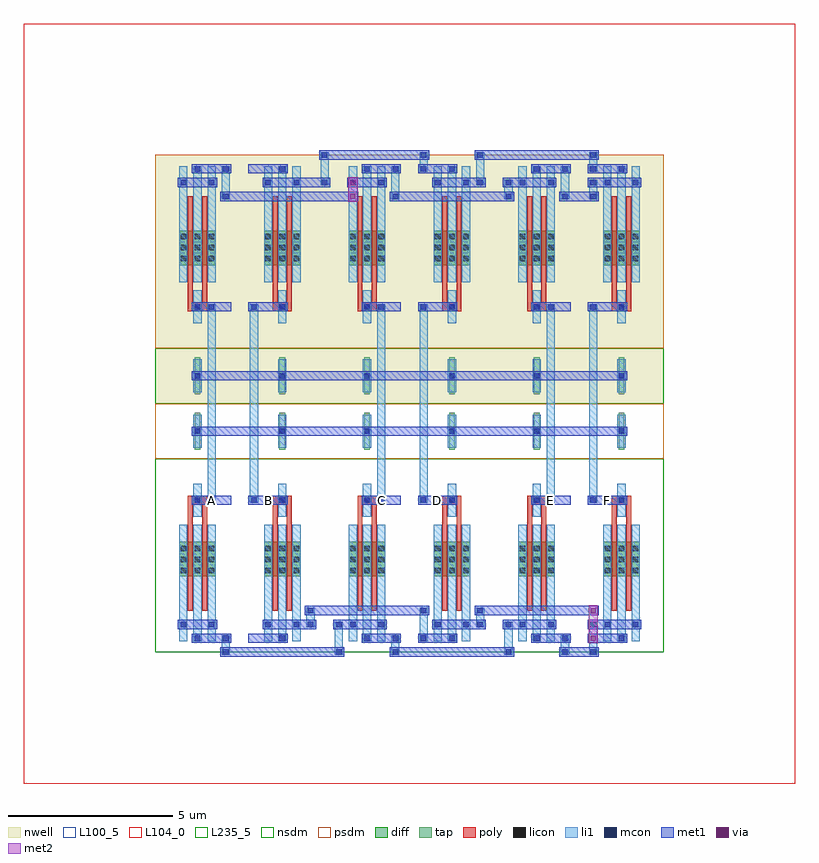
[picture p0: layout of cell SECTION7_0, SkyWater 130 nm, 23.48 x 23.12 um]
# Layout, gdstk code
from math import pi, radians
import gdstk
lib = gdstk.Library(unit=1e-6, precision=1e-09)
def R(c, l, rs):  # rectangles x0, y0, x1, y1
    for r in rs: c.add(gdstk.rectangle(r[:2], r[2:], *l))
def A(c, l, x, y, w, h, nx, ny, dx, dy):  # array of equal rectangles
    R(c, l, [(x+i*dx, y+j*dy, x+i*dx+w, y+j*dy+h) for i in range(nx) for j in range(ny)])
def P(c, l, *ps):  # polygons
    for p in ps: c.add(gdstk.Polygon(p, *l))
nwell = (64, 20)
diff = (65, 20)
tap = (65, 44)
poly = (66, 20)
licon = (66, 44)
li1 = (67, 20)
mcon = (67, 44)
met1 = (68, 20)
via = (68, 44)
met2 = (69, 20)
nsdm = (93, 44)
psdm = (94, 20)
L100_5 = (100, 5)
L104_0 = (104, 0)
L235_5 = (235, 5)

nmos_4t_81744335_x1_y1_1 = lib.new_cell('NMOS_4T_81744335_X1_Y1_1676685742')
R(nmos_4t_81744335_x1_y1_1, diff, [(0.735,2.31,1.845,3.36)])
R(nmos_4t_81744335_x1_y1_1, tap, [(1.205,6.16,1.375,7.28)])
R(nmos_4t_81744335_x1_y1_1, poly, [(1,1.26,1.15,4.62), (1.43,1.26,1.58,4.62), (1,4.485,1.58,4.755)])
A(nmos_4t_81744335_x1_y1_1, licon, 0.775, 2.39, 0.17, 0.17, 3, 3, 0.43, 0.34)
R(nmos_4t_81744335_x1_y1_1, licon, [(1.205,4.535,1.375,4.705), (1.205,6.635,1.375,6.805)])
A(nmos_4t_81744335_x1_y1_1, li1, 0.735, 0.335, 0.25, 3.53, 3, 1, 0.43, 0)
R(nmos_4t_81744335_x1_y1_1, li1, [(1.165,4.115,1.415,5.125), (1.165,6.215,1.415,7.225)])
R(nmos_4t_81744335_x1_y1_1, mcon, [(1.205,0.335,1.375,0.505), (0.775,0.755,0.945,0.925), (1.635,0.755,1.805,0.925), (1.205,4.535,1.375,4.705), (1.205,6.635,1.375,6.805)])
R(nmos_4t_81744335_x1_y1_1, met1, [(0.26,0.28,1.46,0.56), (0.69,0.7,1.89,0.98), (0.26,4.48,1.46,4.76), (0.26,6.58,1.46,6.86)])
R(nmos_4t_81744335_x1_y1_1, nsdm, [(0,0,2.58,5.88)])
R(nmos_4t_81744335_x1_y1_1, psdm, [(0,5.88,2.58,7.56)])
R(nmos_4t_81744335_x1_y1_1, L100_5, [(0,0,2.58,7.56)])

pmos_4t_13952555_x1_y1_1 = lib.new_cell('PMOS_4T_13952555_X1_Y1_1676685743')
R(pmos_4t_13952555_x1_y1_1, nwell, [(0,0,2.58,7.56)])
R(pmos_4t_13952555_x1_y1_1, diff, [(0.735,2.31,1.845,3.36)])
R(pmos_4t_13952555_x1_y1_1, tap, [(1.205,6.16,1.375,7.28)])
R(pmos_4t_13952555_x1_y1_1, poly, [(1,1.26,1.15,4.62), (1.43,1.26,1.58,4.62), (1,4.485,1.58,4.755)])
A(pmos_4t_13952555_x1_y1_1, licon, 0.775, 2.39, 0.17, 0.17, 3, 3, 0.43, 0.34)
R(pmos_4t_13952555_x1_y1_1, licon, [(1.205,4.535,1.375,4.705), (1.205,6.635,1.375,6.805)])
A(pmos_4t_13952555_x1_y1_1, li1, 0.735, 0.335, 0.25, 3.53, 3, 1, 0.43, 0)
R(pmos_4t_13952555_x1_y1_1, li1, [(1.165,4.115,1.415,5.125), (1.165,6.215,1.415,7.225)])
R(pmos_4t_13952555_x1_y1_1, mcon, [(1.205,0.335,1.375,0.505), (0.775,0.755,0.945,0.925), (1.635,0.755,1.805,0.925), (1.205,4.535,1.375,4.705), (1.205,6.635,1.375,6.805)])
R(pmos_4t_13952555_x1_y1_1, met1, [(0.26,0.28,1.46,0.56), (0.69,0.7,1.89,0.98), (0.26,4.48,1.46,4.76), (0.26,6.58,1.46,6.86)])
R(pmos_4t_13952555_x1_y1_1, nsdm, [(0,5.88,2.58,7.56)])
R(pmos_4t_13952555_x1_y1_1, psdm, [(0,0,2.58,5.88)])
R(pmos_4t_13952555_x1_y1_1, L100_5, [(0,0,2.58,7.56)])

section7_0 = lib.new_cell('SECTION7_0')
A(section7_0, li1, 2.025, 0, 0.25, 0.42, 3, 1, 5.16, 0)
A(section7_0, li1, 2.025, 13.86, 0.25, 0.84, 3, 1, 5.16, 0)
R(section7_0, li1, [(2.025,-0.085,2.275,0.085), (2.025,-0.085,2.275,0.085), (5.465,-0.085,5.715,0.085), (5.465,-0.085,5.715,0.085), (7.185,-0.085,7.435,0.085), (7.185,-0.085,7.435,0.085), (10.625,-0.085,10.875,0.085), (10.625,-0.085,10.875,0.085), (12.345,-0.085,12.595,0.085), (12.345,-0.085,12.595,0.085), (13.205,-0.085,13.455,0.085), (13.205,-0.085,13.455,0.085), (5.465,0,5.715,0.84), (10.625,0,10.875,0.84), (13.205,0,13.455,0.84), (2.025,0.335,2.275,0.505), (2.025,0.335,2.275,0.505), (7.185,0.335,7.435,0.505), (7.185,0.335,7.435,0.505), (8.045,0.335,8.295,0.505), (8.045,0.335,8.295,0.505), (12.345,0.335,12.595,0.505), (12.345,0.335,12.595,0.505), (8.045,0.42,8.295,1.26), (4.605,0.755,4.855,0.925), (4.605,0.755,4.855,0.925), (5.465,0.755,5.715,0.925), (5.465,0.755,5.715,0.925), (9.765,0.755,10.015,0.925), (9.765,0.755,10.015,0.925), (10.625,0.755,10.875,0.925), (10.625,0.755,10.875,0.925), (13.205,0.755,13.455,0.925), (13.205,0.755,13.455,0.925), (4.605,0.84,4.855,1.26), (9.765,0.84,10.015,1.26), (4.605,1.175,4.855,1.345), (4.605,1.175,4.855,1.345), (8.045,1.175,8.295,1.345), (8.045,1.175,8.295,1.345), (9.765,1.175,10.015,1.345), (9.765,1.175,10.015,1.345), (1.595,4.535,1.845,4.705), (1.595,4.535,1.845,4.705), (2.885,4.535,3.135,4.705), (2.885,4.535,3.135,4.705), (6.755,4.535,7.005,4.705), (6.755,4.535,7.005,4.705), (8.045,4.535,8.295,4.705), (8.045,4.535,8.295,4.705), (11.915,4.535,12.165,4.705), (11.915,4.535,12.165,4.705), (13.205,4.535,13.455,4.705), (13.205,4.535,13.455,4.705), (1.595,4.62,1.845,10.5), (2.885,4.62,3.135,10.5), (6.755,4.62,7.005,10.5), (8.045,4.62,8.295,10.5), (11.915,4.62,12.165,10.5), (13.205,4.62,13.455,10.5), (1.595,10.415,1.845,10.585), (1.595,10.415,1.845,10.585), (2.885,10.415,3.135,10.585), (2.885,10.415,3.135,10.585), (6.755,10.415,7.005,10.585), (6.755,10.415,7.005,10.585), (8.045,10.415,8.295,10.585), (8.045,10.415,8.295,10.585), (11.915,10.415,12.165,10.585), (11.915,10.415,12.165,10.585), (13.205,10.415,13.455,10.585), (13.205,10.415,13.455,10.585), (2.025,13.775,2.275,13.945), (2.025,13.775,2.275,13.945), (7.185,13.775,7.435,13.945), (7.185,13.775,7.435,13.945), (10.625,13.775,10.875,13.945), (10.625,13.775,10.875,13.945), (12.345,13.775,12.595,13.945), (12.345,13.775,12.595,13.945), (13.205,13.775,13.455,13.945), (13.205,13.775,13.455,13.945), (10.625,13.86,10.875,14.28), (13.205,13.86,13.455,14.28), (5.035,14.195,5.285,14.365), (5.035,14.195,5.285,14.365), (9.765,14.195,10.015,14.365), (9.765,14.195,10.015,14.365), (10.625,14.195,10.875,14.365), (10.625,14.195,10.875,14.365), (13.205,14.195,13.455,14.365), (13.205,14.195,13.455,14.365), (5.035,14.28,5.285,15.12), (9.765,14.28,10.015,15.12), (2.025,14.615,2.275,14.785), (2.025,14.615,2.275,14.785), (7.185,14.615,7.435,14.785), (7.185,14.615,7.435,14.785), (8.045,14.615,8.295,14.785), (8.045,14.615,8.295,14.785), (12.345,14.615,12.595,14.785), (12.345,14.615,12.595,14.785), (13.205,14.615,13.455,14.785), (13.205,14.615,13.455,14.785), (8.045,14.7,8.295,15.12), (13.205,14.7,13.455,15.12), (5.035,15.035,5.285,15.205), (5.035,15.035,5.285,15.205), (8.045,15.035,8.295,15.205), (8.045,15.035,8.295,15.205), (9.765,15.035,10.015,15.205), (9.765,15.035,10.015,15.205), (13.205,15.035,13.455,15.205), (13.205,15.035,13.455,15.205)])
R(section7_0, mcon, [(2.065,-0.085,2.235,0.085), (2.065,-0.085,2.235,0.085), (5.505,-0.085,5.675,0.085), (5.505,-0.085,5.675,0.085), (7.225,-0.085,7.395,0.085), (7.225,-0.085,7.395,0.085), (10.665,-0.085,10.835,0.085), (10.665,-0.085,10.835,0.085), (12.385,-0.085,12.555,0.085), (12.385,-0.085,12.555,0.085), (13.245,-0.085,13.415,0.085), (13.245,-0.085,13.415,0.085), (2.065,0.335,2.235,0.505), (2.065,0.335,2.235,0.505), (7.225,0.335,7.395,0.505), (7.225,0.335,7.395,0.505), (8.085,0.335,8.255,0.505), (8.085,0.335,8.255,0.505), (12.385,0.335,12.555,0.505), (12.385,0.335,12.555,0.505), (4.645,0.755,4.815,0.925), (4.645,0.755,4.815,0.925), (5.505,0.755,5.675,0.925), (5.505,0.755,5.675,0.925), (9.805,0.755,9.975,0.925), (9.805,0.755,9.975,0.925), (10.665,0.755,10.835,0.925), (10.665,0.755,10.835,0.925), (13.245,0.755,13.415,0.925), (13.245,0.755,13.415,0.925), (4.645,1.175,4.815,1.345), (4.645,1.175,4.815,1.345), (8.085,1.175,8.255,1.345), (8.085,1.175,8.255,1.345), (9.805,1.175,9.975,1.345), (9.805,1.175,9.975,1.345), (1.635,4.535,1.805,4.705), (1.635,4.535,1.805,4.705), (2.925,4.535,3.095,4.705), (2.925,4.535,3.095,4.705), (6.795,4.535,6.965,4.705), (6.795,4.535,6.965,4.705), (8.085,4.535,8.255,4.705), (8.085,4.535,8.255,4.705), (11.955,4.535,12.125,4.705), (11.955,4.535,12.125,4.705), (13.245,4.535,13.415,4.705), (13.245,4.535,13.415,4.705), (1.635,10.415,1.805,10.585), (1.635,10.415,1.805,10.585), (2.925,10.415,3.095,10.585), (2.925,10.415,3.095,10.585), (6.795,10.415,6.965,10.585), (6.795,10.415,6.965,10.585), (8.085,10.415,8.255,10.585), (8.085,10.415,8.255,10.585), (11.955,10.415,12.125,10.585), (11.955,10.415,12.125,10.585), (13.245,10.415,13.415,10.585), (13.245,10.415,13.415,10.585), (2.065,13.775,2.235,13.945), (2.065,13.775,2.235,13.945), (7.225,13.775,7.395,13.945), (7.225,13.775,7.395,13.945), (10.665,13.775,10.835,13.945), (10.665,13.775,10.835,13.945), (12.385,13.775,12.555,13.945), (12.385,13.775,12.555,13.945), (13.245,13.775,13.415,13.945), (13.245,13.775,13.415,13.945), (5.075,14.195,5.245,14.365), (5.075,14.195,5.245,14.365), (9.805,14.195,9.975,14.365), (9.805,14.195,9.975,14.365), (10.665,14.195,10.835,14.365), (10.665,14.195,10.835,14.365), (13.245,14.195,13.415,14.365), (13.245,14.195,13.415,14.365), (2.065,14.615,2.235,14.785), (2.065,14.615,2.235,14.785), (7.225,14.615,7.395,14.785), (7.225,14.615,7.395,14.785), (8.085,14.615,8.255,14.785), (8.085,14.615,8.255,14.785), (12.385,14.615,12.555,14.785), (12.385,14.615,12.555,14.785), (13.245,14.615,13.415,14.785), (13.245,14.615,13.415,14.785), (5.075,15.035,5.245,15.205), (5.075,15.035,5.245,15.205), (8.085,15.035,8.255,15.205), (8.085,15.035,8.255,15.205), (9.805,15.035,9.975,15.205), (9.805,15.035,9.975,15.205), (13.245,15.035,13.415,15.205), (13.245,15.035,13.415,15.205)])
A(section7_0, met1, 2.15, 6.58, 0.86, 0.28, 3, 2, 5.16, 1.68)
R(section7_0, met1, [(1.98,-0.14,2.32,0.14), (1.98,-0.14,2.32,0.14), (2.15,-0.14,5.59,0.14), (5.42,-0.14,5.76,0.14), (5.42,-0.14,5.76,0.14), (7.14,-0.14,7.48,0.14), (7.14,-0.14,7.48,0.14), (7.31,-0.14,10.75,0.14), (10.58,-0.14,10.92,0.14), (10.58,-0.14,10.92,0.14), (12.3,-0.14,12.64,0.14), (12.3,-0.14,12.64,0.14), (12.47,-0.14,13.33,0.14), (13.16,-0.14,13.5,0.14), (13.16,-0.14,13.5,0.14), (1.98,0.28,2.32,0.56), (1.98,0.28,2.32,0.56), (7.14,0.28,7.48,0.56), (7.14,0.28,7.48,0.56), (8,0.28,8.34,0.56), (8,0.28,8.34,0.56), (12.3,0.28,12.64,0.56), (12.3,0.28,12.64,0.56), (13.17,0.28,13.49,0.56), (13.17,0.28,13.49,0.56), (4.3,0.7,4.73,0.98), (4.56,0.7,4.9,0.98), (4.56,0.7,4.9,0.98), (5.42,0.7,5.76,0.98), (5.42,0.7,5.76,0.98), (5.59,0.7,6.02,0.98), (9.46,0.7,9.89,0.98), (9.72,0.7,10.06,0.98), (9.72,0.7,10.06,0.98), (10.58,0.7,10.92,0.98), (10.58,0.7,10.92,0.98), (10.75,0.7,11.18,0.98), (13.16,0.7,13.5,0.98), (13.16,0.7,13.5,0.98), (13.33,0.7,13.76,0.98), (4.56,1.12,4.9,1.4), (4.56,1.12,4.9,1.4), (4.73,1.12,8.17,1.4), (8,1.12,8.34,1.4), (8,1.12,8.34,1.4), (9.72,1.12,10.06,1.4), (9.72,1.12,10.06,1.4), (9.89,1.12,13.33,1.4), (13.17,1.12,13.49,1.4), (13.17,1.12,13.49,1.4), (1.55,4.48,1.89,4.76), (1.55,4.48,1.89,4.76), (2.84,4.48,3.18,4.76), (2.84,4.48,3.18,4.76), (6.71,4.48,7.05,4.76), (6.71,4.48,7.05,4.76), (8,4.48,8.34,4.76), (8,4.48,8.34,4.76), (11.87,4.48,12.21,4.76), (11.87,4.48,12.21,4.76), (13.16,4.48,13.5,4.76), (13.16,4.48,13.5,4.76), (3.87,6.58,6.45,6.86), (9.03,6.58,11.61,6.86), (3.87,8.26,6.45,8.54), (9.03,8.26,11.61,8.54), (1.55,10.36,1.89,10.64), (1.55,10.36,1.89,10.64), (2.84,10.36,3.18,10.64), (2.84,10.36,3.18,10.64), (6.71,10.36,7.05,10.64), (6.71,10.36,7.05,10.64), (8,10.36,8.34,10.64), (8,10.36,8.34,10.64), (11.87,10.36,12.21,10.64), (11.87,10.36,12.21,10.64), (13.16,10.36,13.5,10.64), (13.16,10.36,13.5,10.64), (1.98,13.72,2.32,14), (1.98,13.72,2.32,14), (2.15,13.72,6.02,14), (5.86,13.72,6.18,14), (5.86,13.72,6.18,14), (7.14,13.72,7.48,14), (7.14,13.72,7.48,14), (7.31,13.72,10.75,14), (10.58,13.72,10.92,14), (10.58,13.72,10.92,14), (12.3,13.72,12.64,14), (12.3,13.72,12.64,14), (12.47,13.72,13.33,14), (13.16,13.72,13.5,14), (13.16,13.72,13.5,14), (4.3,14.14,5.16,14.42), (4.99,14.14,5.33,14.42), (4.99,14.14,5.33,14.42), (5.86,14.14,6.18,14.42), (5.86,14.14,6.18,14.42), (9.46,14.14,9.89,14.42), (9.72,14.14,10.06,14.42), (9.72,14.14,10.06,14.42), (10.58,14.14,10.92,14.42), (10.58,14.14,10.92,14.42), (10.75,14.14,11.18,14.42), (13.16,14.14,13.5,14.42), (13.16,14.14,13.5,14.42), (13.33,14.14,13.76,14.42), (1.98,14.56,2.32,14.84), (1.98,14.56,2.32,14.84), (7.14,14.56,7.48,14.84), (7.14,14.56,7.48,14.84), (8,14.56,8.34,14.84), (8,14.56,8.34,14.84), (12.3,14.56,12.64,14.84), (12.3,14.56,12.64,14.84), (13.16,14.56,13.5,14.84), (13.16,14.56,13.5,14.84), (4.99,14.98,5.33,15.26), (4.99,14.98,5.33,15.26), (5.16,14.98,8.17,15.26), (8,14.98,8.34,15.26), (8,14.98,8.34,15.26), (9.72,14.98,10.06,15.26), (9.72,14.98,10.06,15.26), (9.89,14.98,13.33,15.26), (13.16,14.98,13.5,15.26), (13.16,14.98,13.5,15.26)])
P(section7_0, met1, [(0,0),(0,0),(0,0),(0,0)],
  [(0,0),(0,0),(0,0),(0,0)],
  [(0,0),(0,0),(0,0),(0,0)],
  [(0,0),(0,0),(0,0),(0,0)],
  [(0,0),(0,0),(0,0),(0,0)],
  [(0,0),(0,0),(0,0),(0,0)],
  [(0,0),(0,0),(0,0),(0,0)],
  [(0,0),(0,0),(0,0),(0,0)],
  [(0,0),(0,0),(0,0),(0,0)],
  [(0,0),(0,0),(0,0),(0,0)],
  [(0,0),(0,0),(0,0),(0,0)],
  [(0,0),(0,0),(0,0),(0,0)],
  [(0,0),(0,0),(0,0),(0,0)],
  [(0,0),(0,0),(0,0),(0,0)],
  [(0,0),(0,0),(0,0),(0,0)],
  [(0,0),(0,0),(0,0),(0,0)],
  [(0,0),(0,0),(0,0),(0,0)],
  [(0,0),(0,0),(0,0),(0,0)],
  [(0,0),(0,0),(0,0),(0,0)],
  [(0,0),(0,0),(0,0),(0,0)],
  [(0,0),(0,0),(0,0),(0,0)],
  [(0,0),(0,0),(0,0),(0,0)],
  [(0,0),(0,0),(0,0),(0,0)],
  [(0,0),(0,0),(0,0),(0,0)],
  [(0,0),(0,0),(0,0),(0,0)],
  [(0,0),(0,0),(0,0),(0,0)],
  [(0,0),(0,0),(0,0),(0,0)],
  [(0,0),(0,0),(0,0),(0,0)],
  [(0,0),(0,0),(0,0),(0,0)],
  [(0,0),(0,0),(0,0),(0,0)],
  [(0,0),(0,0),(0,0),(0,0)],
  [(0,0),(0,0),(0,0),(0,0)],
  [(0,0),(0,0),(0,0),(0,0)],
  [(0,0),(0,0),(0,0),(0,0)],
  [(0,0),(0,0),(0,0),(0,0)],
  [(0,0),(0,0),(0,0),(0,0)],
  [(0,0),(0,0),(0,0),(0,0)],
  [(0,0),(0,0),(0,0),(0,0)],
  [(0,0),(0,0),(0,0),(0,0)],
  [(0,0),(0,0),(0,0),(0,0)],
  [(0,0),(0,0),(0,0),(0,0)],
  [(0,0),(0,0),(0,0),(0,0)],
  [(0,0),(0,0),(0,0),(0,0)],
  [(0,0),(0,0),(0,0),(0,0)],
  [(0,0),(0,0),(0,0),(0,0)],
  [(0,0),(0,0),(0,0),(0,0)],
  [(0,0),(0,0),(0,0),(0,0)],
  [(0,0),(0,0),(0,0),(0,0)],
  [(0,0),(0,0),(0,0),(0,0)],
  [(0,0),(0,0),(0,0),(0,0)],
  [(0,0),(0,0),(0,0),(0,0)],
  [(0,0),(0,0),(0,0),(0,0)],
  [(0,0),(0,0),(0,0),(0,0)],
  [(0,0),(0,0),(0,0),(0,0)])
R(section7_0, via, [(13.255,0.345,13.405,0.495), (13.255,0.345,13.405,0.495), (13.255,1.185,13.405,1.335), (13.255,1.185,13.405,1.335), (5.945,13.785,6.095,13.935), (5.945,13.785,6.095,13.935), (5.945,14.205,6.095,14.355), (5.945,14.205,6.095,14.355)])
R(section7_0, met2, [(13.19,0.26,13.47,0.58), (13.19,0.26,13.47,0.58), (13.19,0.42,13.47,1.26), (13.19,1.1,13.47,1.42), (13.19,1.1,13.47,1.42), (5.88,13.7,6.16,14.02), (5.88,13.7,6.16,14.02), (5.88,13.86,6.16,14.28), (5.88,14.12,6.16,14.44), (5.88,14.12,6.16,14.44)])
R(section7_0, L104_0, [(-4,-4,19.48,19.12)])
R(section7_0, L235_5, [(0,0,15.48,15.12)])
section7_0.add(gdstk.Reference(nmos_4t_81744335_x1_y1_1, (7.74,0), rotation=pi, x_reflection=True))
section7_0.add(gdstk.Reference(nmos_4t_81744335_x1_y1_1, (12.9,0), rotation=pi, x_reflection=True))
section7_0.add(gdstk.Reference(nmos_4t_81744335_x1_y1_1, (7.74,0)))
section7_0.add(gdstk.Reference(nmos_4t_81744335_x1_y1_1, (12.9,0)))
section7_0.add(gdstk.Reference(nmos_4t_81744335_x1_y1_1, (2.58,0), rotation=pi, x_reflection=True))
section7_0.add(gdstk.Reference(nmos_4t_81744335_x1_y1_1, (2.58,0)))
section7_0.add(gdstk.Reference(pmos_4t_13952555_x1_y1_1, (12.9,15.12), rotation=pi))
section7_0.add(gdstk.Reference(pmos_4t_13952555_x1_y1_1, (2.58,15.12), x_reflection=True))
section7_0.add(gdstk.Reference(pmos_4t_13952555_x1_y1_1, (7.74,15.12), rotation=pi))
section7_0.add(gdstk.Reference(pmos_4t_13952555_x1_y1_1, (7.74,15.12), x_reflection=True))
section7_0.add(gdstk.Reference(pmos_4t_13952555_x1_y1_1, (12.9,15.12), x_reflection=True))
section7_0.add(gdstk.Reference(pmos_4t_13952555_x1_y1_1, (2.58,15.12), rotation=pi))
section7_0.add(gdstk.Label('C', (6.88,4.62), layer=68, texttype=5))
section7_0.add(gdstk.Label('E', (12.04,4.62), layer=68, texttype=5))
section7_0.add(gdstk.Label('D', (8.6,4.62), layer=68, texttype=5))
section7_0.add(gdstk.Label('F', (13.76,4.62), layer=68, texttype=5))
section7_0.add(gdstk.Label('A', (1.72,4.62), layer=68, texttype=5))
section7_0.add(gdstk.Label('B', (3.44,4.62), layer=68, texttype=5))

lib.write_gds('SECTION7_0.gds')
